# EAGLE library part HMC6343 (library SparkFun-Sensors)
Honeywell compass IC with tilt compensation, SEN-08656

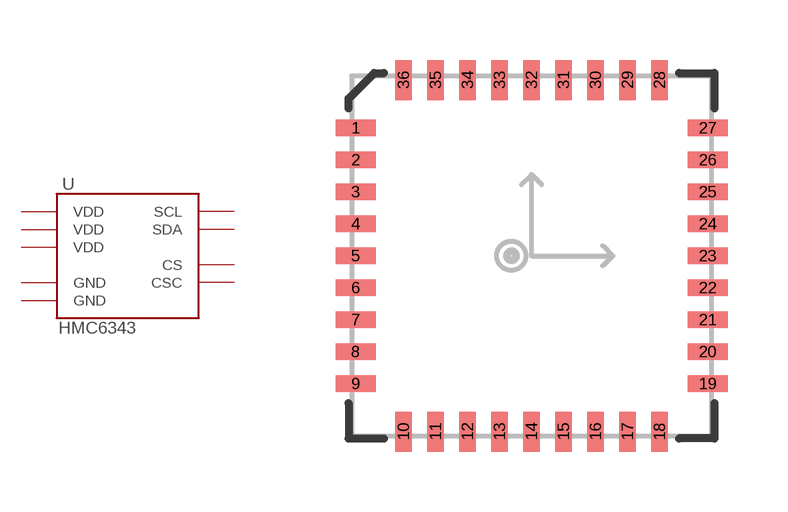
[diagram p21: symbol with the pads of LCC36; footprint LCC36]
Designator prefix -

## HMC6343A  [LCC36]
3  VDD
11  VDD
21  VDD
22  CS
25  GND
29  GND
32  SCL
35  CSC
36  SDA

## Footprint LCC36 (pad centres in mm)
smd 1 x 0.42: 1 -4.4,3.2; 2 -4.4,2.4; 3 -4.4,1.6; 4 -4.4,0.8; 5 -4.4,0; 6 -4.4,-0.8; 7 -4.4,-1.6; 8 -4.4,-2.4; 9 -4.4,-3.2; 19 4.4,-3.2; 20 4.4,-2.4; 21 4.4,-1.6; 22 4.4,-0.8; 23 4.4,0; 24 4.4,0.8; 25 4.4,1.6; 26 4.4,2.4; 27 4.4,3.2
smd 0.42 x 1: 10 -3.2,-4.4; 11 -2.4,-4.4; 12 -1.6,-4.4; 13 -0.8,-4.4; 14 0,-4.4; 15 0.8,-4.4; 16 1.6,-4.4; 17 2.4,-4.4; 18 3.2,-4.4; 28 3.2,4.4; 29 2.4,4.4; 30 1.6,4.4; 31 0.8,4.4; 32 0,4.4; 33 -0.8,4.4; 34 -1.6,4.4; 35 -2.4,4.4; 36 -3.2,4.4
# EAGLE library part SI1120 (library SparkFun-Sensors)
Si1120: Proximity/Ambient Light Sensor

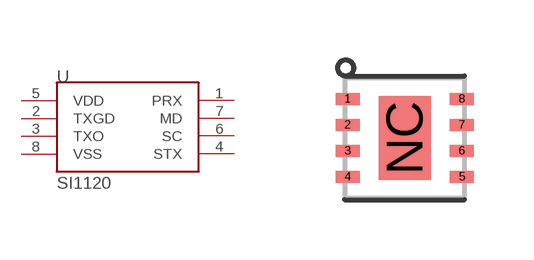
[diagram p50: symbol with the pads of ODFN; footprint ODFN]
Designator prefix -

## SI1120  [ODFN]
1  PRX
2  TXGD
3  TXO
4  STX
5  VDD
6  SC
7  MD
8  VSS

## Footprint ODFN (pad centres in mm)
ODFN: 1.5mm x 1.5mm. Used on the Si1120
smd 0.6 x 0.3: 1 -1.43,0.975; 2 -1.43,0.325; 3 -1.43,-0.325; 4 -1.43,-0.975; 5 1.43,-0.975; 6 1.43,-0.325; 7 1.43,0.325; 8 1.43,0.975
smd 1.3 x 2.1: NC 0,0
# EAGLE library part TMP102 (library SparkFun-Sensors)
I2C degC temp sensor

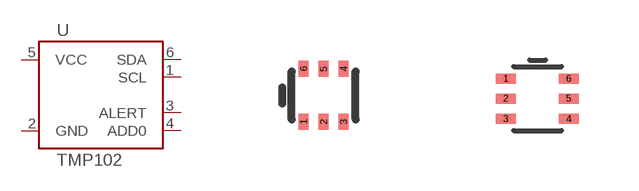
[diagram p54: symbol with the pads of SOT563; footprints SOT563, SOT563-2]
Designator prefix U

## TMP102 (PROD_ID: IC-09303; VALUE: TMP102)  [SOT563]
1  SCL
2  GND
3  ALERT
4  ADD0
5  VCC
6  SDA

## TMP1021:1  [SOT563-2]
Pads as for SOT563

## Footprint SOT563 (pad centres in mm)
smd 0.25 x 0.4: 1 -0.5,-0.66; 2 0,-0.66; 3 0.5,-0.66; 4 0.5,0.66; 5 0,0.66; 6 -0.5,0.67

## Footprint SOT563-2 (pad centres in mm)
smd 0.508 x 0.249: 1 -0.8,0.498; 2 -0.8,0.003; 3 -0.8,-0.506; 4 0.776,-0.506; 5 0.776,0.003; 6 0.776,0.498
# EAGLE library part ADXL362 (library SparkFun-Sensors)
Micropower 3-axis accelerometer 2/4/8g digital output (SPI) IC-11297

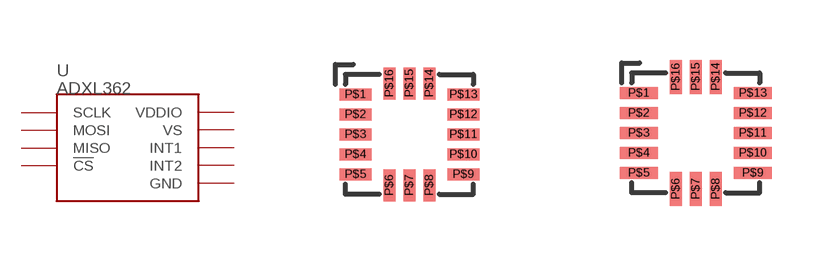
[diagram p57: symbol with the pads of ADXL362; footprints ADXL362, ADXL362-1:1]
Designator prefix U

## ADXL362 (PROD_ID: IC-11297; VALUE: ADXL362)  [ADXL362]
P$1  VDDIO
P$4  SCLK
P$6  MOSI
P$7  MISO
P$8  !CS
P$9  INT2
P$11  INT1
P$12  GND
P$13  GND
P$14  VS
P$16  GND

## ADXL362ADXL362-1:1  [ADXL362-1:1]
Pads as for ADXL362

## Footprint ADXL362 (pad centres in mm)
smd 0.8 x 0.3: P$1 -1.35,1; P$2 -1.35,0.5; P$3 -1.35,0; P$4 -1.35,-0.5; P$5 -1.35,-1; P$9 1.35,-1; P$10 1.35,-0.5; P$11 1.35,0; P$12 1.35,0.5; P$13 1.35,1
smd 0.3 x 0.8: P$6 -0.5,-1.275; P$7 0,-1.275; P$8 0.5,-1.275; P$14 0.5,1.275; P$15 0,1.275; P$16 -0.5,1.275

## Footprint ADXL362-1:1 (pad centres in mm)
smd 0.952 x 0.3: P$1 -1.426,1; P$2 -1.426,0.5; P$3 -1.426,0; P$4 -1.426,-0.5; P$5 -1.426,-1; P$9 1.426,-1; P$10 1.426,-0.5; P$11 1.426,0; P$12 1.426,0.5; P$13 1.426,1
smd 0.3 x 0.851: P$6 -0.5,-1.402; P$7 0,-1.402; P$8 0.5,-1.402; P$14 0.5,1.402; P$15 0,1.402; P$16 -0.5,1.402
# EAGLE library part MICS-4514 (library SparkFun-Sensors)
Metal oxide MEMS carbon monoxide (CO) and NOx sensor in an SMD package.

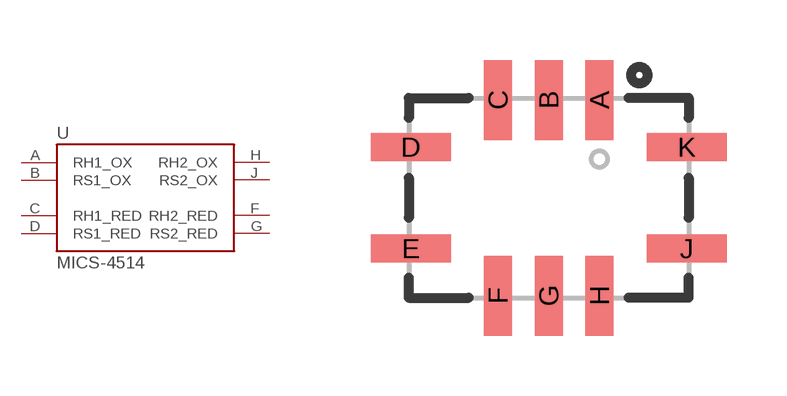
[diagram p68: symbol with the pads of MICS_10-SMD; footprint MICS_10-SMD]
Designator prefix -

## MICS-4514 (PROD_ID: COMP-12310)  [MICS_10-SMD]
A  RH1_OX
B  RS1_OX
C  RH1_RED
D  RS1_RED
F  RH2_RED
G  RS2_RED
H  RH2_OX
J  RS2_OX

## Footprint MICS_10-SMD (pad centres in mm)
smd 0.7 x 2: A 1.27,2.45; B 0,2.45; C -1.27,2.45; F -1.27,-2.45; G 0,-2.45; H 1.27,-2.45
smd 2 x 0.7: D -3.45,1.27; E -3.45,-1.27; J 3.45,-1.27; K 3.45,1.27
